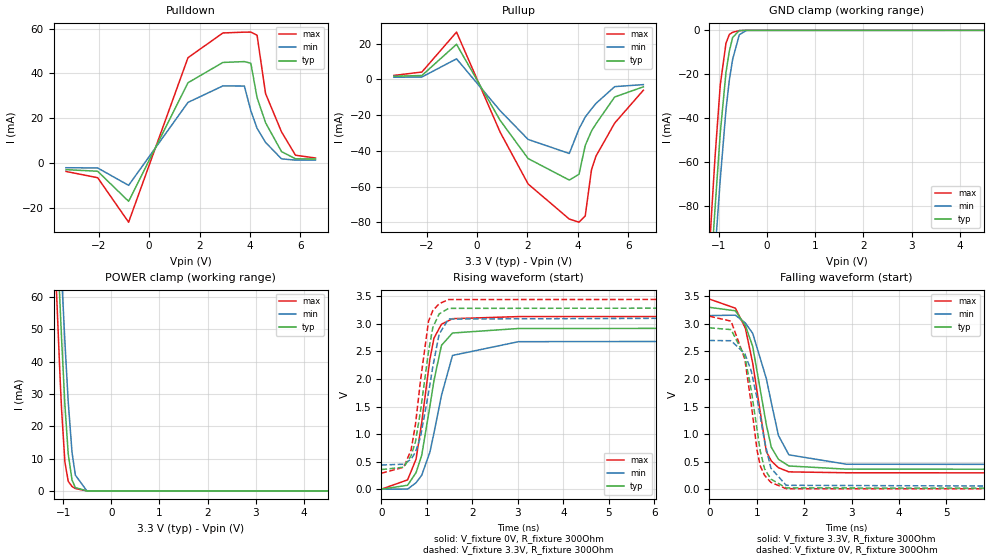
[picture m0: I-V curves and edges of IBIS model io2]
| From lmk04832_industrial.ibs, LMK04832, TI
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|   io2 Model
[Model]   io2
Model_type   I/O
Polarity   Non-Inverting
Enable   Active-High
Vinl = 0.4
Vinh = 1.2
Vmeas = 1.65
Vref = 0
Cref = 2pF
Rref = 100000
|   typ   min   max
C_comp   0.9542pF   0.8946pF   1.0084pF
|  Where Nom  PVT is Nominal Process,   3.3V,  25C
|   Fast PVT is Strong Process,   3.45V, -40C
|   Slow PVT is Weak Process,   3.15V, 85C
[Model spec]
|subparameter
Vinl   0.400   0.370   0.430
Vinh   1.200   1.170   1.230
[Voltage Range]   3.3   3.15   3.45
|Junction Temperature
[Temperature Range]   25   85   -40
[Pullup Reference]   3.3   3.15   3.45
[Pulldown Reference]   -0   0   0
[Power Clamp Reference]   3.3   3.15   3.45
[GND Clamp Reference]   0   0   0
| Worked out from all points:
|   slope of the pulldown table from 0 to 0.495 V, typ, clamps not added: 36.9 ohm
|   slope of the pullup table from 0 to 0.495 V, typ, clamps not added: 38.5 ohm
|   GND clamp passes 1 mA (typ) near -0.66 V on its own axis
|   POWER clamp passes 1 mA (typ) near -0.74 V on its own axis
|   falling waveform, V_fixture 3.3V, R_fixture 300Ohm: 20-80 % time 373ps typ, 427ps min, 342ps max; typ from 3.3 V to 0.356 V
|   rising waveform, V_fixture 0V, R_fixture 300Ohm: 20-80 % time 356ps typ, 419ps min, 312ps max; typ from 0 V to 2.93 V
|   rising waveform, V_fixture 3.3V, R_fixture 300Ohm: 20-80 % time 304ps typ, 341ps min, 277ps max; typ from 0.356 V to 3.3 V
|   falling waveform, V_fixture 0V, R_fixture 300Ohm: 20-80 % time 328ps typ, 363ps min, 307ps max; typ from 2.93 V to 0 V
[Pulldown]
|   Voltage   I(typ)   I(min)   I(max)
-3.3V     -2.925mA   -2.061mA   -3.731mA
-2.043V   -3.639mA   -2.172mA   -6.516mA
-815.1mV  -17.05mA   -9.924mA   -26.36mA
1.541V    35.84mA    27.07mA    47.01mA
2.927V    44.9mA     34.44mA    58.05mA
3.779V    45.28mA    34.37mA    58.42mA
4.036V    44.54mA    23.32mA    58.44mA
4.283V    29.22mA    15.53mA    57.05mA
4.62V     18.02mA    9.231mA    31.01mA
5.254V    5.108mA    1.894mA    13.91mA
5.808V    1.925mA    1.333mA    3.509mA
6.6V      1.809mA    1.319mA    2.28mA
[GND Clamp]
|   Voltage   I(typ)   I(min)   I(max)
-3.3V     -902.1mA   -861.1mA   -952.1mA
-1.211V   -125.1mA   -142.3mA   -104.7mA
-1.162V   -107.8mA   -126.2mA   -86.09mA
-1.102V   -87.51mA   -107.1mA   -64.56mA
-1.082V   -80.89mA   -100.9mA   -57.65mA
-973.5mV  -46.68mA   -67.7mA    -24.83mA
-854.7mV  -19.11mA   -36.2mA    -5.85mA
-785.4mV  -9.484mA   -22.65mA   -1.894mA
-716.1mV  -3.231mA   -13.14mA   -887.1uA
-577.5mV  -106.4uA   -1.982mA   -109.8uA
-429mV    -2.249uA   -30.81uA   -2.533uA
6.6V      0A         0A         0A
[Pullup]
|   Voltage   I(typ)   I(min)   I(max)
-3.3V     1.751mA    1.214mA    2.227mA
-2.191V   2.176mA    1.329mA    4.118mA
-815.1mV  19.66mA    11.52mA    26.5mA
917.4mV   -22.98mA   -17.54mA   -29.59mA
2.026V    -44.34mA   -33.62mA   -58.58mA
3.66V     -56.38mA   -41.5mA    -78.22mA
4.046V    -53.13mA   -27.7mA    -79.98mA
4.293V    -37.01mA   -21.1mA    -76.48mA
4.541V    -28.92mA   -16.54mA   -50.6mA
4.719V    -24.89mA   -13.46mA   -43mA
5.462V    -9.845mA   -4.052mA   -24.46mA
6.6V      -4.158mA   -2.92mA    -6.06mA
[POWER Clamp]
|   Voltage   I(typ)   I(min)   I(max)
-3.3V     919.5mA    881mA      965.2mA
-1.181V   98.38mA    115.8mA    78mA
-1.142V   84.24mA    102.5mA    62.96mA
-1.082V   63.61mA    82.89mA    41.42mA
-1.063V   56.95mA    76.49mA    34.68mA
-1.033V   47.23mA    67.06mA    25.24mA
-963.6mV  26.56mA    46.04mA    8.896mA
-894.3mV  11.34mA    27.39mA    2.97mA
-815.1mV  3.349mA    11.84mA    1.354mA
-745.8mV  1.029mA    4.874mA    740.7uA
-508.2mV  13.75uA    32.81uA    13.03uA
6.6V      0A         0A         0A
[Ramp]
R_load = 300
|   typ   min   max
dV/dt_r   1.75683/3.5474e-10   1.61907/4.16702e-10   1.8835/3.11056e-10
dV/dt_f   1.76634/3.72026e-10   1.6268/4.26819e-10   1.89612/3.40812e-10
[Falling Waveform]
V_fixture = 3.3V
V_fixture_min = 3.15V
V_fixture_max = 3.45V
R_fixture = 300Ohm
C_fixture = 0F
|   Time   V(typ)   V(min)   V(max)
0s        3.3V       3.15V      3.45V
549.2ps   3.237V     3.158V     3.284V
760.5ps   2.969V     3.014V     2.92V
914.9ps   2.59V      2.828V     2.285V
1.203ns   1.168V     2.004V     680.2mV
1.306ns   763.1mV    1.575V     513mV
1.458ns   541.2mV    973.5mV    389.2mV
1.678ns   421mV      623mV      313.9mV
2.895ns   363.1mV    452.4mV    297.6mV
25ns      356.1mV    438.7mV    289.8mV
[Rising Waveform]
V_fixture = 0V
V_fixture_min = 0V
V_fixture_max = 0V
R_fixture = 300Ohm
C_fixture = 0F
|   Time   V(typ)   V(min)   V(max)
0s        2.167nV    3.702nV    2.094nV
574.4ps   70.98mV    842.3uV    168.6mV
760.5ps   299.1mV    116.5mV    543.5mV
885.5ps   617mV      253mV      1.212V
1.064ns   1.501V     669.8mV    2.354V
1.154ns   1.97V      1.018V     2.74V
1.319ns   2.61V      1.702V     2.993V
1.562ns   2.834V     2.427V     3.094V
3.015ns   2.916V     2.677V     3.132V
25ns      2.928V     2.698V     3.139V
[Rising Waveform]
V_fixture = 3.3V
V_fixture_min = 3.15V
V_fixture_max = 3.45V
R_fixture = 300Ohm
C_fixture = 0F
|   Time   V(typ)   V(min)   V(max)
0s        356.1mV    438.7mV    289.8mV
490ps     398.1mV    452.8mV    397.3mV
652.5ps   609.2mV    544.6mV    714.1mV
748.7ps   863.1mV    674.9mV    1.181V
857.4ps   1.411V     941.7mV    1.964V
1.034ns   2.496V     1.744V     3.047V
1.129ns   2.935V     2.223V     3.241V
1.268ns   3.18V      2.814V     3.365V
1.474ns   3.281V     3.088V     3.441V
25ns      3.3V       3.15V      3.45V
[Falling Waveform]
|Gnd
V_fixture = 0V
V_fixture_min = 0V
V_fixture_max = 0V
R_fixture = 300Ohm
C_fixture = 0F
|   Time   V(typ)   V(min)   V(max)
0s        2.928V     2.698V     3.139V
457.9ps   2.896V     2.694V     3.049V
748.7ps   2.409V     2.46V      2.36V
885.5ps   1.791V     2.141V     1.531V
1.006ns   1.084V     1.649V     708.9mV
1.074ns   689.8mV    1.32V      422.4mV
1.165ns   369.8mV    867.6mV    249.9mV
1.298ns   182.8mV    383.6mV    123.3mV
1.621ns   22.48mV    69.87mV    8.575mV
25ns      3.342nV    6.022nV    2.941nV
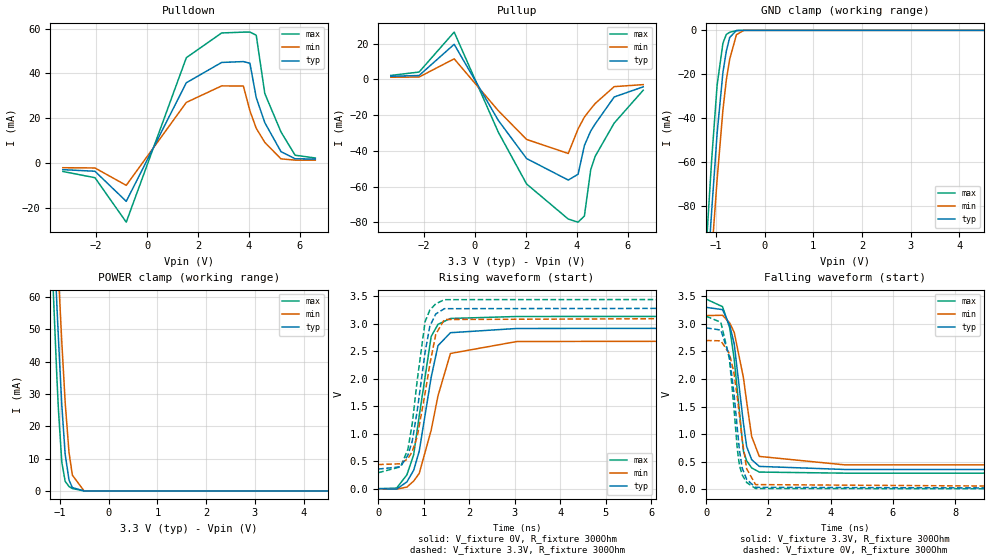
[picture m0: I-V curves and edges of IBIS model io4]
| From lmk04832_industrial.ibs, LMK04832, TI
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|   io4 Model
[Model]   io4
Model_type   I/O
Polarity   Non-Inverting
Enable   Active-High
Vinl = 0.4
Vinh = 1.2
Vmeas = 1.65
Vref = 0
Cref = 2pF
Rref = 100000
|   typ   min   max
C_comp   0.9542pF   0.8946pF   1.0084pF
|  Where Nom  PVT is Nominal Process,   3.3V,  25C
|   Fast PVT is Strong Process,   3.45V, -40C
|   Slow PVT is Weak Process,   3.15V, 85C
[Model spec]
|subparameter
Vinl   0.400   0.370   0.430
Vinh   1.200   1.170   1.230
[Voltage Range]   3.3   3.15   3.45
|Junction Temperature
[Temperature Range]   25   85   -40
[Pullup Reference]   3.3   3.15   3.45
[Pulldown Reference]   0   0   0
[Power Clamp Reference]   3.3   3.15   3.45
[GND Clamp Reference]   0   0   0
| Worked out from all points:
|   slope of the pulldown table from 0 to 0.495 V, typ, clamps not added: 36.9 ohm
|   slope of the pullup table from 0 to 0.495 V, typ, clamps not added: 38.5 ohm
|   GND clamp passes 1 mA (typ) near -0.66 V on its own axis
|   POWER clamp passes 1 mA (typ) near -0.74 V on its own axis
|   falling waveform, V_fixture 3.3V, R_fixture 300Ohm: 20-80 % time 372ps typ, 427ps min, 341ps max; typ from 3.3 V to 0.356 V
|   rising waveform, V_fixture 0V, R_fixture 300Ohm: 20-80 % time 355ps typ, 419ps min, 312ps max; typ from 0 V to 2.93 V
|   rising waveform, V_fixture 3.3V, R_fixture 300Ohm: 20-80 % time 304ps typ, 340ps min, 277ps max; typ from 0.356 V to 3.3 V
|   falling waveform, V_fixture 0V, R_fixture 300Ohm: 20-80 % time 328ps typ, 363ps min, 308ps max; typ from 2.93 V to 0 V
[Pulldown]
|   Voltage   I(typ)   I(min)   I(max)
-3.3V     -2.925mA   -2.061mA   -3.731mA
-2.043V   -3.639mA   -2.172mA   -6.516mA
-815.1mV  -17.05mA   -9.924mA   -26.36mA
1.541V    35.84mA    27.07mA    47.01mA
2.927V    44.9mA     34.44mA    58.05mA
3.779V    45.28mA    34.37mA    58.42mA
4.036V    44.54mA    23.32mA    58.44mA
4.283V    29.22mA    15.53mA    57.05mA
4.62V     18.02mA    9.231mA    31.01mA
5.254V    5.108mA    1.894mA    13.91mA
5.808V    1.925mA    1.333mA    3.509mA
6.6V      1.809mA    1.319mA    2.28mA
[GND Clamp]
|   Voltage   I(typ)   I(min)   I(max)
-3.3V     -902.1mA   -861.1mA   -952.1mA
-1.211V   -125.1mA   -142.3mA   -104.7mA
-1.162V   -107.8mA   -126.2mA   -86.09mA
-1.102V   -87.51mA   -107.1mA   -64.56mA
-1.082V   -80.89mA   -100.9mA   -57.65mA
-973.5mV  -46.68mA   -67.7mA    -24.83mA
-854.7mV  -19.11mA   -36.2mA    -5.85mA
-785.4mV  -9.484mA   -22.65mA   -1.894mA
-716.1mV  -3.231mA   -13.14mA   -887.1uA
-577.5mV  -106.4uA   -1.982mA   -109.8uA
-429mV    -2.249uA   -30.81uA   -2.533uA
6.6V      0A         0A         0A
[Pullup]
|   Voltage   I(typ)   I(min)   I(max)
-3.3V     1.751mA    1.214mA    2.227mA
-2.191V   2.176mA    1.329mA    4.118mA
-815.1mV  19.66mA    11.52mA    26.5mA
917.4mV   -22.98mA   -17.54mA   -29.59mA
2.026V    -44.34mA   -33.62mA   -58.58mA
3.66V     -56.38mA   -41.5mA    -78.22mA
4.046V    -53.13mA   -27.7mA    -79.98mA
4.293V    -37.01mA   -21.1mA    -76.48mA
4.541V    -28.92mA   -16.54mA   -50.6mA
4.719V    -24.89mA   -13.46mA   -43mA
5.462V    -9.845mA   -4.052mA   -24.46mA
6.6V      -4.158mA   -2.92mA    -6.06mA
[POWER Clamp]
|   Voltage   I(typ)   I(min)   I(max)
-3.3V     919.5mA    881mA      965.2mA
-1.181V   98.38mA    115.8mA    78mA
-1.142V   84.24mA    102.5mA    62.96mA
-1.082V   63.61mA    82.89mA    41.42mA
-1.063V   56.95mA    76.49mA    34.68mA
-1.033V   47.23mA    67.06mA    25.24mA
-963.6mV  26.56mA    46.04mA    8.896mA
-894.3mV  11.34mA    27.39mA    2.97mA
-815.1mV  3.349mA    11.84mA    1.354mA
-745.8mV  1.029mA    4.874mA    740.7uA
-508.2mV  13.75uA    32.81uA    13.03uA
6.6V      0A         0A         0A
[Ramp]
R_load = 300
|   typ   min   max
dV/dt_r   1.75683/3.54779e-10   1.61907/4.16956e-10   1.8835/3.11191e-10
dV/dt_f   1.76634/3.7192e-10   1.6268/4.26813e-10   1.89612/3.40733e-10
[Falling Waveform]
V_fixture = 3.3V
V_fixture_min = 3.15V
V_fixture_max = 3.45V
R_fixture = 300Ohm
C_fixture = 0F
|   Time   V(typ)   V(min)   V(max)
0s        3.3V       3.15V      3.45V
527.3ps   3.258V     3.156V     3.312V
757.2ps   2.974V     3.017V     2.928V
902.7ps   2.636V     2.846V     2.354V
1.198ns   1.198V     2.026V     693.5mV
1.303ns   771.6mV    1.585V     514.5mV
1.463ns   535.6mV    957mV      386.3mV
1.708ns   413mV      594.3mV    310.3mV
4.459ns   357.4mV    440.8mV    290.4mV
25ns      356.1mV    438.7mV    289.8mV
[Rising Waveform]
V_fixture = 0V
V_fixture_min = 0V
V_fixture_max = 0V
R_fixture = 300Ohm
C_fixture = 0F
|   Time   V(typ)   V(min)   V(max)
0s        2.414nV    4.078nV    2.041nV
404.7ps   -7.578mV   -9.074mV   10.26mV
631.2ps   123.1mV    29.07mV    251.4mV
780.8ps   335.9mV    138.7mV    619.7mV
902.6ps   682.4mV    278.4mV    1.325V
1.165ns   2.026V     1.063V     2.769V
1.315ns   2.602V     1.689V     2.99V
1.589ns   2.838V     2.46V      3.097V
3.053ns   2.915V     2.678V     3.133V
25ns      2.928V     2.698V     3.139V
[Rising Waveform]
V_fixture = 3.3V
V_fixture_min = 3.15V
V_fixture_max = 3.45V
R_fixture = 300Ohm
C_fixture = 0F
|   Time   V(typ)   V(min)   V(max)
0s        356.1mV    438.7mV    289.8mV
490ps     398.2mV    452.8mV    397.3mV
652.5ps   609.2mV    544.6mV    714.1mV
748.7ps   863.2mV    674.9mV    1.18V
860.6ps   1.431V     952.7mV    1.987V
1.031ns   2.479V     1.731V     3.038V
1.135ns   2.954V     2.261V     3.25V
1.266ns   3.179V     2.808V     3.364V
1.456ns   3.275V     3.078V     3.439V
25ns      3.3V       3.15V      3.45V
[Falling Waveform]
|Gnd
V_fixture = 0V
V_fixture_min = 0V
V_fixture_max = 0V
R_fixture = 300Ohm
C_fixture = 0F
|   Time   V(typ)   V(min)   V(max)
0s        2.928V     2.698V     3.139V
473.6ps   2.887V     2.692V     3.029V
748.7ps   2.411V     2.46V      2.364V
888.9ps   1.772V     2.13V      1.509V
1.003ns   1.099V     1.66V      723.1mV
1.07ns    710.3mV    1.34V      433.5mV
1.159ns   383.4mV    896.9mV    257.9mV
1.304ns   176.3mV    369mV      120.2mV
1.589ns   32.79mV    82.99mV    12.39mV
25ns      2.435nV    4.2nV      3.162nV
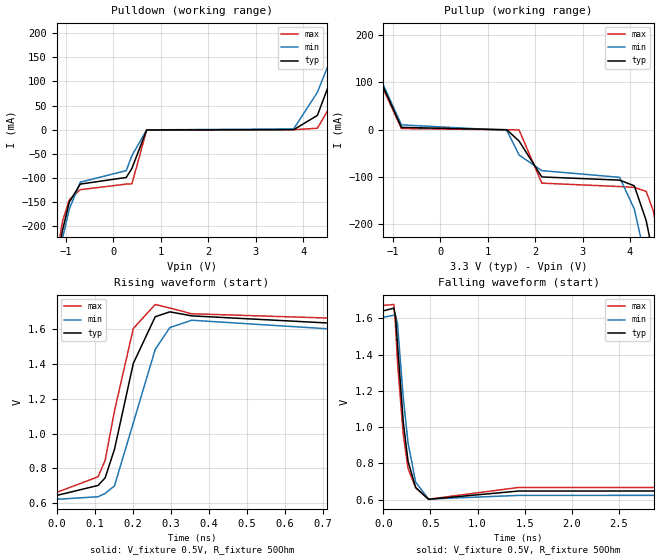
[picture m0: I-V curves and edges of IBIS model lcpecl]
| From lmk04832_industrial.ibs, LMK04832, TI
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|   lcpecl Model
[Model]   lcpecl
Model_type   Output
Polarity   Non-Inverting
Vmeas = 1.2
Vref = 0.5
Cref = 1pF
Rref = 50
|   typ   min   max
C_comp   2.136pF   2.117pF   2.176pF
|  Where Nom  PVT is Nominal Process,   3.3V,  25C
|   Fast PVT is Strong Process,   3.45V, -40C
|   Slow PVT is Weak Process,   3.15V, 85C
[Voltage Range]   3.3   3.15   3.45
[Temperature Range]   25   85   -40
[Pullup Reference]   3.3   3.15   3.45
[Pulldown Reference]   0   0   0
[Power Clamp Reference]   3.3   3.15   3.45
[GND Clamp Reference]   0   0   0
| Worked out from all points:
|   slope of the pulldown table from 0 to 0.495 V, typ, clamps not added: 8.72 ohm
|   falling waveform, V_fixture 0.5V, R_fixture 50Ohm: 20-80 % time 101ps typ, 112ps min, 93.1ps max; typ from 1.64 V to 0.647 V
|   rising waveform, V_fixture 0.5V, R_fixture 50Ohm: 20-80 % time 62.5ps typ, 71.8ps min, 54ps max; typ from 0.646 V to 1.64 V
[Pulldown]
|   Voltage   I(typ)   I(min)   I(max)
-3.3V     -1.634A    -1.565A    -1.72A
-1.58V    -478.1mA   -480.7mA   -477.9mA
-1.07V    -206.7mA   -223.5mA   -188.4mA
-930mV    -149.9mA   -164.2mA   -144.9mA
-700mV    -112.6mA   -108.6mA   -124.2mA
270mV     -98.88mA   -84.73mA   -112.6mA
390mV     -79.94mA   -53.52mA   -112.1mA
700mV     -463.1uA   -308.1uA   -622.7uA
3.8V      66.61uA    1.78mA     3.397uA
4.3V      29.75mA    77.53mA    3.11mA
4.59V     105.4mA    149.1mA    51.91mA
6.6V      677.6mA    668.1mA    689.6mA
[Pullup]
|   Voltage   I(typ)   I(min)   I(max)
-3.3V     677.5mA    629mA      737.8mA
-1.38V    130.1mA    134.1mA    125mA
-820mV    4.971mA    10.37mA    2.473mA
1.4V      -6.996uA   -1.344mA   -902.9pA
1.66V     -23.77mA   -53.41mA   -434.4uA
2.14V     -99.7mA    -86.31mA   -112.8mA
3.78V     -106.4mA   -100.5mA   -120mA
4.09V     -118.4mA   -167.4mA   -121.7mA
4.34V     -191.7mA   -279.1mA   -130.2mA
4.49V     -265.6mA   -352mA     -171.1mA
4.68V     -365.7mA   -451.2mA   -270.1mA
6.6V      -1.633A    -1.645A    -1.623A
[Ramp]
R_load = 50
|   typ   min   max
dV/dt_r   0.59723/6.22411e-11   0.589578/7.15093e-11   0.604767/5.37425e-11
dV/dt_f   0.597067/1.00645e-10   0.58945/1.12275e-10   0.604583/9.31093e-11
[Falling Waveform]
V_fixture = 0.5V
V_fixture_min = 0.5V
V_fixture_max = 0.5V
R_fixture = 50Ohm
C_fixture = 0F
|   Time   V(typ)   V(min)   V(max)
0s        1.642V     1.607V     1.672V
111.1ps   1.657V     1.618V     1.677V
128.6ps   1.613V     1.616V     1.56V
149.6ps   1.459V     1.572V     1.359V
211ps     1.029V     1.163V     958.5mV
262.1ps   811.3mV    912mV      771.3mV
342.6ps   667.3mV    696.9mV    665.8mV
480ps     602.1mV    603.7mV    602.9mV
1.436ns   648mV      623.8mV    667.6mV
20ns      646.9mV    624.7mV    664.3mV
[Rising Waveform]
V_fixture = 0.5V
V_fixture_min = 0.5V
V_fixture_max = 0.5V
R_fixture = 50Ohm
C_fixture = 0F
|   Time   V(typ)   V(min)   V(max)
0s        645.5mV    623.5mV    662.7mV
109.3ps   703mV      638.3mV    752.6mV
127.9ps   746.4mV    657mV      846.1mV
152.5ps   910.1mV    700.5mV    1.13V
202ps     1.401V     1.061V     1.601V
259.6ps   1.668V     1.481V     1.738V
298.1ps   1.696V     1.606V     1.718V
355.6ps   1.673V     1.648V     1.685V
706.7ps   1.633V     1.6V       1.661V
20ns      1.641V     1.606V     1.671V
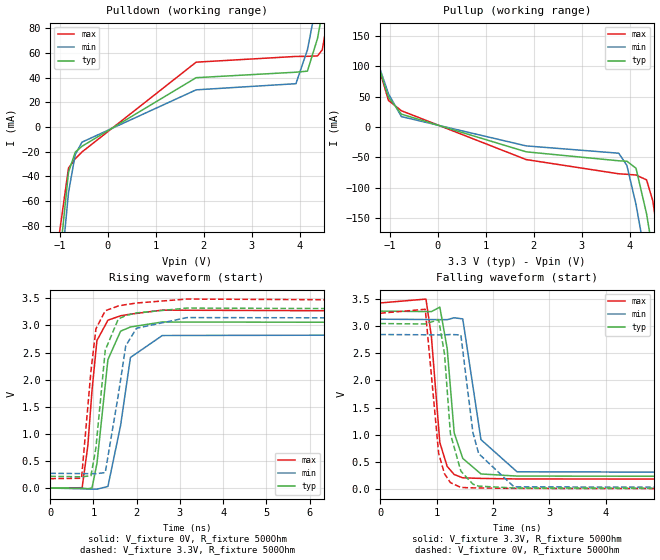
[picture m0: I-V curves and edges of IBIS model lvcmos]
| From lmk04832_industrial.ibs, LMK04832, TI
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|   lvcmos Model
[Model]   lvcmos
Model_type   Output
Polarity   Non-Inverting
Vmeas = 1.65
Vref = 0
Cref = 1pF
Rref = 100000
|   typ   min   max
C_comp   2.136pF   2.117pF   2.176pF
|  Where Nom  PVT is Nominal Process,   3.3V,  25C
|   Fast PVT is Strong Process,   3.45V, -40C
|   Slow PVT is Weak Process,   3.15V, 85C
[Voltage Range]   3.3   3.15   3.45
|Junction Temperature
[Temperature Range]   25   85   -40
[Pullup Reference]   3.3   3.15   3.45
[Pulldown Reference]   0   0   0
[Power Clamp Reference]   3.3   3.15   3.45
[GND Clamp Reference]   0   0   0
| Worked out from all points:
|   slope of the pulldown table from 0 to 0.495 V, typ, clamps not added: 36.5 ohm
|   slope of the pullup table from 0 to 0.495 V, typ, clamps not added: 38.4 ohm
|   falling waveform, V_fixture 3.3V, R_fixture 500Ohm: 20-80 % time 190ps typ, 232ps min, 153ps max; typ from 3.27 V to 0.222 V
|   rising waveform, V_fixture 0V, R_fixture 500Ohm: 20-80 % time 243ps typ, 301ps min, 200ps max; typ from 0.005 V to 3.04 V
|   rising waveform, V_fixture 3.3V, R_fixture 500Ohm: 20-80 % time 232ps typ, 282ps min, 190ps max; typ from 0.222 V to 3.27 V
|   falling waveform, V_fixture 0V, R_fixture 500Ohm: 20-80 % time 187ps typ, 245ps min, 149ps max; typ from 3.04 V to 0.005 V
[Pulldown]
|   Voltage   I(typ)   I(min)   I(max)
-3.3V     -1.539A    -1.482A    -1.617A
-1.04V    -120mA     -143.3mA   -94.45mA
-820mV    -36.54mA   -53.04mA   -33.13mA
-680mV    -20.29mA   -22.31mA   -25.69mA
-540mV    -15.52mA   -12.18mA   -20.16mA
1.84V     40.09mA    30.24mA    52.67mA
3.92V     44.55mA    35.23mA    57.32mA
4.16V     45.4mA     62.7mA     57.42mA
4.37V     71.89mA    104.9mA    57.75mA
4.47V     93.24mA    126.3mA    62.72mA
4.79V     168mA      199.6mA    135.4mA
6.6V      678.6mA    668.6mA    691.6mA
[Pullup]
|   Voltage   I(typ)   I(min)   I(max)
-3.3V     677.8mA    628.9mA    738.4mA
-1.57V    183.8mA    180.4mA    190.2mA
-1.03V    49.29mA    55.1mA     44.09mA
-760mV    21.42mA    17.37mA    27.03mA
1.84V     -40.65mA   -30.88mA   -53.41mA
3.77V     -55.44mA   -42.96mA   -76.86mA
3.94V     -56.16mA   -63.04mA   -77.67mA
4.13V     -67.66mA   -127.4mA   -78.86mA
4.35V     -142.7mA   -224.2mA   -86.87mA
4.48V     -204.8mA   -284.9mA   -121.3mA
4.79V     -363.1mA   -447.7mA   -286.4mA
6.6V      -1.539A    -1.567A    -1.519A
[Ramp]
R_load = 500
|   typ   min   max
dV/dt_r   1.82166/2.40324e-10   1.70082/2.98157e-10   1.93581/1.96123e-10
dV/dt_f   1.82808/1.86535e-10   1.70663/2.28249e-10   1.9437/1.52417e-10
[Falling Waveform]
V_fixture = 3.3V
V_fixture_min = 3.15V
V_fixture_max = 3.45V
R_fixture = 500Ohm
C_fixture = 0F
|   Time   V(typ)   V(min)   V(max)
0s        3.269V     3.121V     3.419V
810.8ps   3.261V     3.115V     3.49V
906.9ps   3.26V      3.114V     2.809V
1.057ns   3.342V     3.113V     858.4mV
1.187ns   2.587V     3.112V     422.4mV
1.312ns   1.036V     3.147V     273.4mV
1.464ns   568.6mV    3.126V     212.6mV
1.787ns   283.8mV    912.9mV    201.9mV
2.427ns   244.6mV    323.4mV    191.8mV
20ns      222.4mV    277mV      179.2mV
[Rising Waveform]
V_fixture = 0V
V_fixture_min = 0V
V_fixture_max = 0V
R_fixture = 500Ohm
C_fixture = 0F
|   Time   V(typ)   V(min)   V(max)
0s        5.266mV    5.886mV    4.566mV
737.2ps   5.508mV    -7.992mV   12.57mV
869.1ps   -6.55mV    -10.47mV   785.7mV
965.4ps   7.217mV    -12.29mV   1.8V
1.08ns    458.7mV    -14.45mV   2.722V
1.334ns   2.371V     35.89mV    3.096V
1.627ns   2.894V     1.158V     3.177V
1.855ns   2.971V     2.41V      3.208V
2.592ns   3.063V     2.814V     3.281V
20ns      3.041V     2.841V     3.231V
[Rising Waveform]
V_fixture = 3.3V
V_fixture_min = 3.15V
V_fixture_max = 3.45V
R_fixture = 500Ohm
C_fixture = 0F
|   Time   V(typ)   V(min)   V(max)
0s        222.4mV    277mV      179.2mV
723.1ps   212.7mV    272.6mV    186.3mV
941.9ps   233.4mV    271.2mV    2.165V
1.057ns   752.7mV    270.5mV    2.938V
1.272ns   2.544V     290.5mV    3.27V
1.574ns   3.118V     1.72V      3.358V
1.746ns   3.181V     2.623V     3.382V
1.995ns   3.23V      2.948V     3.412V
3.164ns   3.319V     3.144V     3.485V
20ns      3.27V      3.122V     3.42V
[Falling Waveform]
|Gnd
V_fixture = 0V
V_fixture_min = 0V
V_fixture_max = 0V
R_fixture = 500Ohm
C_fixture = 0F
|   Time   V(typ)   V(min)   V(max)
0s        3.041V     2.84V      3.23V
798.4ps   3.033V     2.835V     3.303V
1.036ns   3.113V     2.833V     661.5mV
1.14ns    2.486V     2.833V     287.2mV
1.245ns   1.02V      2.84V      124.1mV
1.43ns    335.3mV    2.833V     36.04mV
1.644ns   96.02mV    1.044V     28.36mV
1.746ns   60.54mV    657.2mV    26.9mV
2.374ns   25.97mV    46.73mV    17.95mV
20ns      5.283mV    5.88mV     4.566mV
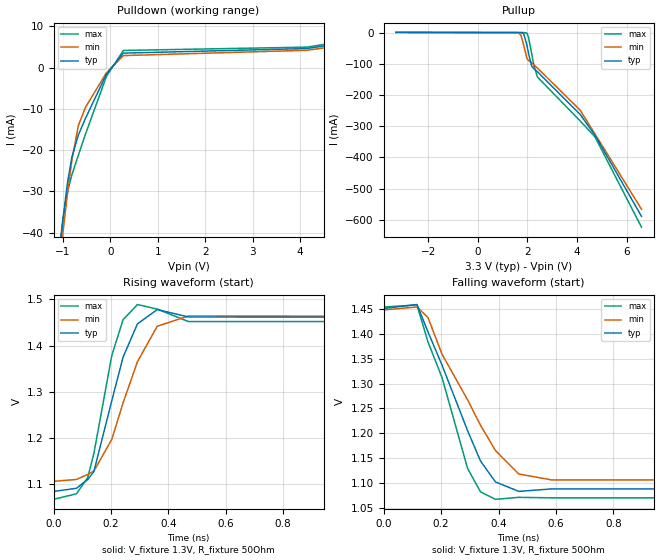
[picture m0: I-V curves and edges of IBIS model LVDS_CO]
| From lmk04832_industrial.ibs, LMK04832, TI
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|   LVDS_CO Model
[Model]   LVDS_CO
Model_type   Output
Polarity   Non-Inverting
Vmeas = 1.243
Vref = 1.243
Cref = 1pF
Rref = 50
|   typ   min   max
C_comp   2.136pF   2.117pF   2.176pF
|  Where Nom  PVT is Nominal Process,   3.3V,  25C
|   Fast PVT is Strong Process,   3.45V, -40C
|   Slow PVT is Weak Process,   3.15V, 85C
[Voltage Range]   3.3   3.15   3.45
[Temperature Range]   25   85   -40
[Pullup Reference]   3.3   3.15   3.45
[Pulldown Reference]   0   0   0
[Power Clamp Reference]   3.3   3.15   3.45
[GND Clamp Reference]   0   0   0
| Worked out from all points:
|   slope of the pulldown table from 0 to 0.495 V, typ, clamps not added: 117 ohm
|   slope of the pullup table from 0 to 0.495 V, typ, clamps not added: 61.7 kohm
|   falling waveform, V_fixture 1.3V, R_fixture 50Ohm: 20-80 % time 156ps typ, 191ps min, 125ps max; typ from 1.45 V to 1.08 V
|   rising waveform, V_fixture 1.3V, R_fixture 50Ohm: 20-80 % time 85.9ps typ, 111ps min, 68.6ps max; typ from 1.08 V to 1.45 V
[Pulldown]
|   Voltage   I(typ)   I(min)   I(max)
-3.3V     -338.5mA   -314.6mA   -367.2mA
-1.181V   -56.59mA   -59.61mA   -55.2mA
-1.122V   -49.58mA   -52.9mA    -48.57mA
-1.003V   -36.78mA   -40.09mA   -36.93mA
-904.2mV  -27.8mA    -30.32mA   -30.01mA
-815.1mV  -21.77mA   -22.63mA   -26.06mA
-676.5mV  -16.35mA   -14.09mA   -21.24mA
-528mV    -12.36mA   -9.687mA   -16.19mA
-82.5mV   -1.606mA   -1.251mA   -2.127mA
273.9mV   3.482mA    2.885mA    4.132mA
4.145V    4.593mA    4.173mA    4.933mA
6.6V      8.728mA    7.964mA    9.299mA
[Pullup]
|   Voltage   I(typ)   I(min)   I(max)
-3.3V     1.103mA    965.2uA    1.257mA
1.63V     526.5uA    71.87uA    556.6uA
1.739V    459.6uA    -7.885mA   555.7uA
1.848V    -2.918mA   -39.34mA   551.6uA
1.977V    -38.84mA   -82.32mA   -1.077mA
2.046V    -67.1mA    -89.03mA   -14.98mA
2.175V    -107.8mA   -97.18mA   -68.73mA
2.264V    -115.6mA   -103.2mA   -105.4mA
2.402V    -125.1mA   -113.3mA   -141.9mA
4.125V    -261.8mA   -248.3mA   -282.8mA
4.729V    -329.2mA   -325.4mA   -334.6mA
6.6V      -588.9mA   -566mA     -623.7mA
[Ramp]
R_load = 50
|   typ   min   max
dV/dt_r   0.220258/8.58833e-11   0.205319/1.11418e-10   0.232267/6.86471e-11
dV/dt_f   0.220258/1.5584e-10   0.205319/1.91325e-10   0.232267/1.24892e-10
[Falling Waveform]
V_fixture = 1.3V
V_fixture_min = 1.3V
V_fixture_max = 1.3V
R_fixture = 50Ohm
C_fixture = 0F
|   Time   V(typ)   V(min)   V(max)
0s        1.451V     1.448V     1.454V
115.9ps   1.459V     1.454V     1.458V
154.1ps   1.404V     1.433V     1.384V
203.2ps   1.337V     1.359V     1.312V
292.4ps   1.205V     1.267V     1.129V
337.4ps   1.144V     1.216V     1.082V
389.6ps   1.102V     1.165V     1.067V
470.5ps   1.083V     1.118V     1.071V
585.8ps   1.088V     1.106V     1.07V
20ns      1.084V     1.106V     1.067V
[Rising Waveform]
V_fixture = 1.3V
V_fixture_min = 1.3V
V_fixture_max = 1.3V
R_fixture = 50Ohm
C_fixture = 0F
|   Time   V(typ)   V(min)   V(max)
0s        1.084V     1.106V     1.067V
80ps      1.091V     1.11V      1.079V
119.1ps   1.11V      1.121V     1.114V
140.5ps   1.127V     1.128V     1.166V
203.2ps   1.281V     1.197V     1.379V
242.4ps   1.375V     1.276V     1.456V
292.4ps   1.447V     1.365V     1.489V
361.3ps   1.478V     1.442V     1.479V
470.5ps   1.462V     1.464V     1.452V
20ns      1.451V     1.448V     1.454V
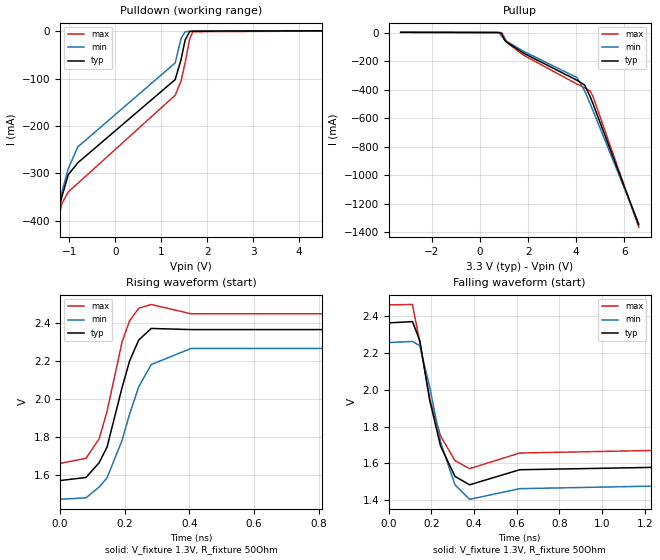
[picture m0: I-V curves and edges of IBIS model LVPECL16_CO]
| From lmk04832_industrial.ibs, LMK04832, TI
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|   LVPECL16_CO Model
[Model]   LVPECL16_CO
Model_type   Output
Polarity   Non-Inverting
Vmeas = 1.7
Vref = 1.3
Cref = 1pF
Rref = 50
|   typ   min   max
C_comp   2.136pF   2.117pF   2.176pF
|  Where Nom  PVT is Nominal Process,   3.3V,  25C
|   Fast PVT is Strong Process,   3.45V, -40C
|   Slow PVT is Weak Process,   3.15V, 85C
[Voltage Range]   3.3   3.15   3.45
[Temperature Range]   25   85   -40
[Pullup Reference]   3.3   3.15   3.45
[Pulldown Reference]   0   -0   -0
[Power Clamp Reference]   3.3   3.15   3.45
[GND Clamp Reference]   0   0   0
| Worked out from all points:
|   slope of the pulldown table from 0 to 0.495 V, typ, clamps not added: 12.2 ohm
|   falling waveform, V_fixture 1.3V, R_fixture 50Ohm: 20-80 % time 80.4ps typ, 85.3ps min, 82ps max; typ from 2.37 V to 1.57 V
|   rising waveform, V_fixture 1.3V, R_fixture 50Ohm: 20-80 % time 74.9ps typ, 93.6ps min, 64.2ps max; typ from 1.57 V to 2.37 V
[Pulldown]
|   Voltage   I(typ)   I(min)   I(max)
-3.3V     -1.296A    -1.223A    -1.392A
-1.468V   -476.7mA   -460.2mA   -498.3mA
-1.29V    -400.6mA   -388.9mA   -416.1mA
-1.162V   -348.5mA   -339.1mA   -363.5mA
-1.023V   -302.4mA   -289.5mA   -338.6mA
-815.1mV  -277.4mA   -243.9mA   -320.7mA
1.304V    -102.1mA   -67.03mA   -135.1mA
1.432V    -59.76mA   -15.28mA   -105.4mA
1.521V    -18.65mA   -1.629mA   -66.45mA
1.62V     -1.008mA   -76.58uA   -15.66mA
1.69V     -74.44uA   -8.576uA   -1.234mA
6.6V      1.265mA    1.305mA    1.216mA
[Pullup]
|   Voltage   I(typ)   I(min)   I(max)
-3.3V     1.264mA    1.234mA    1.291mA
709.5mV   -12.34uA   -200.5uA   -99.85nA
818.4mV   -764uA     -4.966mA   -19.81uA
907.5mV   -12.3mA    -27.71mA   -1.465mA
1.036V    -57.2mA    -54.41mA   -42.82mA
1.125V    -68.63mA   -63.05mA   -72.07mA
1.818V    -145.4mA   -132.3mA   -159.5mA
4.036V    -335mA     -316.4mA   -361.6mA
4.353V    -368.4mA   -410.1mA   -388.1mA
4.58V     -449.5mA   -499.6mA   -409.5mA
4.689V    -495.1mA   -543.5mA   -443.4mA
6.6V      -1.347A    -1.341A    -1.364A
[Ramp]
R_load = 50
|   typ   min   max
dV/dt_r   0.476611/7.4869e-11   0.472189/9.35527e-11   0.481185/6.41902e-11
dV/dt_f   0.476611/8.03532e-11   0.472189/8.5317e-11   0.481185/8.19353e-11
[Falling Waveform]
V_fixture = 1.3V
V_fixture_min = 1.15V
V_fixture_max = 1.45V
R_fixture = 50Ohm
C_fixture = 0F
|   Time   V(typ)   V(min)   V(max)
0s        2.365V     2.258V     2.463V
111.1ps   2.372V     2.264V     2.465V
145.1ps   2.27V      2.241V     2.26V
191.9ps   1.944V     2.016V     1.951V
243ps     1.694V     1.716V     1.749V
310.2ps   1.53V      1.484V     1.616V
378.7ps   1.484V     1.405V     1.572V
613.7ps   1.566V     1.463V     1.657V
1.241ns   1.579V     1.477V     1.671V
20ns      1.571V     1.472V     1.661V
[Rising Waveform]
V_fixture = 1.3V
V_fixture_min = 1.15V
V_fixture_max = 1.45V
R_fixture = 50Ohm
C_fixture = 0F
|   Time   V(typ)   V(min)   V(max)
0s        1.571V     1.472V     1.661V
80ps      1.587V     1.48V      1.688V
120.8ps   1.665V     1.537V     1.791V
145.1ps   1.747V     1.585V     1.935V
191.9ps   2.062V     1.784V     2.302V
215.1ps   2.201V     1.922V     2.412V
243ps     2.31V      2.064V     2.477V
281.8ps   2.371V     2.181V     2.497V
405.1ps   2.365V     2.266V     2.448V
20ns      2.365V     2.258V     2.463V
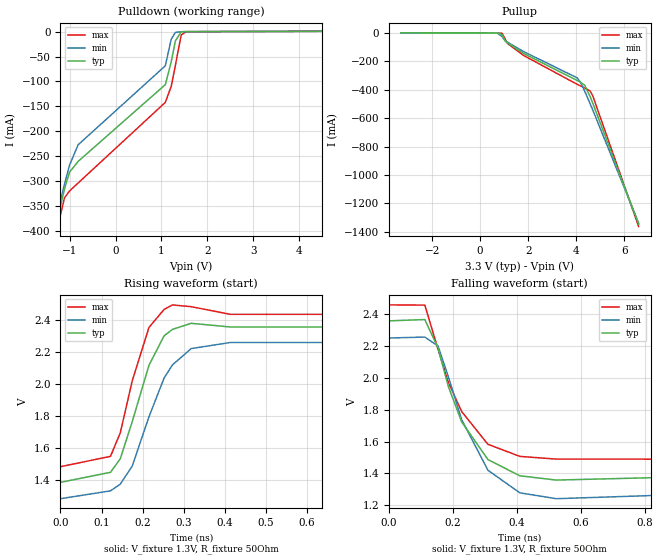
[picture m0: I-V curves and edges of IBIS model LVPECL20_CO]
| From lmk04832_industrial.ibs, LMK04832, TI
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|   LVPECL20_CO Model
[Model]   LVPECL20_CO
Model_type   Output
Polarity   Non-Inverting
Vmeas = 1.7
Vref = 1.3
Cref = 1pF
Rref = 50
|   typ   min   max
C_comp   2.136pF   2.117pF   2.176pF
|  Where Nom  PVT is Nominal Process,   3.3V,  25C
|   Fast PVT is Strong Process,   3.45V, -40C
|   Slow PVT is Weak Process,   3.15V, 85C
[Voltage Range]   3.3   3.15   3.45
[Temperature Range]   25   85   -40
[Pullup Reference]   3.3   3.15   3.45
[Pulldown Reference]   0   0   0
[Power Clamp Reference]   3.3   3.15   3.45
[GND Clamp Reference]   0   0   0
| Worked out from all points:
|   slope of the pulldown table from 0 to 0.495 V, typ, clamps not added: 12.3 ohm
|   falling waveform, V_fixture 1.3V, R_fixture 50Ohm: 20-80 % time 112ps typ, 109ps min, 120ps max; typ from 2.36 V to 1.39 V
|   rising waveform, V_fixture 1.3V, R_fixture 50Ohm: 20-80 % time 68.5ps typ, 83.3ps min, 58.1ps max; typ from 1.39 V to 2.36 V
[Pulldown]
|   Voltage   I(typ)   I(min)   I(max)
-3.3V     -1.282A    -1.209A    -1.378A
-1.468V   -462.7mA   -446mA     -484.7mA
-1.29V    -386.5mA   -374.7mA   -402.3mA
-1.112V   -315.4mA   -306.2mA   -333.6mA
-1.003V   -282.1mA   -268.2mA   -319.8mA
-815.1mV  -260.4mA   -227.1mA   -303.7mA
1.086V    -106.3mA   -68.5mA    -141.9mA
1.214V    -60.68mA   -15.11mA   -109.8mA
1.304V    -18.84mA   -1.578mA   -68.08mA
1.432V    -332.6uA   -28.92uA   -6.656mA
1.541V    -5.208uA   -914.2nA   -44.93uA
6.6V      1.265mA    1.305mA    1.216mA
[Pullup]
|   Voltage   I(typ)   I(min)   I(max)
-3.3V     1.264mA    1.234mA    1.292mA
709.5mV   -9.812uA   -156.1uA   -79.96nA
907.5mV   -10.69mA   -24.91mA   -1.168mA
1.036V    -56.13mA   -53.92mA   -40.68mA
1.135V    -69.55mA   -64.4mA    -73.16mA
1.818V    -144.9mA   -131.7mA   -159.1mA
4.036V    -334.5mA   -315.8mA   -361.1mA
4.165V    -345.2mA   -344mA     -371.9mA
4.353V    -367.9mA   -409.6mA   -387.6mA
4.58V     -449mA     -499mA     -409mA
4.689V    -494.7mA   -543mA     -443mA
6.6V      -1.347A    -1.34A     -1.364A
[Ramp]
R_load = 50
|   typ   min   max
dV/dt_r   0.583216/6.8525e-11   0.579476/8.33029e-11   0.58404/5.81231e-11
dV/dt_f   0.583216/1.11813e-10   0.579476/1.08916e-10   0.58404/1.19557e-10
[Falling Waveform]
V_fixture = 1.3V
V_fixture_min = 1.15V
V_fixture_max = 1.45V
R_fixture = 50Ohm
C_fixture = 0F
|   Time   V(typ)   V(min)   V(max)
0s        2.359V     2.251V     2.459V
111.9ps   2.367V     2.257V     2.458V
153.3ps   2.188V     2.201V     2.18V
185.7ps   1.945V     2.007V     1.972V
227.1ps   1.724V     1.738V     1.789V
309.3ps   1.487V     1.42V      1.583V
409ps     1.385V     1.278V     1.507V
522.9ps   1.358V     1.241V     1.49V
1.262ns   1.395V     1.29V      1.489V
20ns      1.387V     1.285V     1.485V
[Rising Waveform]
V_fixture = 1.3V
V_fixture_min = 1.15V
V_fixture_max = 1.45V
R_fixture = 50Ohm
C_fixture = 0F
|   Time   V(typ)   V(min)   V(max)
0s        1.387V     1.285V     1.485V
121.9ps   1.45V      1.334V     1.55V
145.7ps   1.535V     1.376V     1.697V
174.8ps   1.767V     1.489V     2.022V
215.5ps   2.119V     1.797V     2.356V
252.4ps   2.304V     2.04V      2.469V
272.8ps   2.344V     2.122V     2.497V
318.4ps   2.382V     2.224V     2.486V
413.9ps   2.359V     2.262V     2.438V
20ns      2.359V     2.251V     2.459V
